VERSION 5.7 ;
  NOWIREEXTENSIONATPIN ON ;
  DIVIDERCHAR "/" ;
  BUSBITCHARS "[]" ;
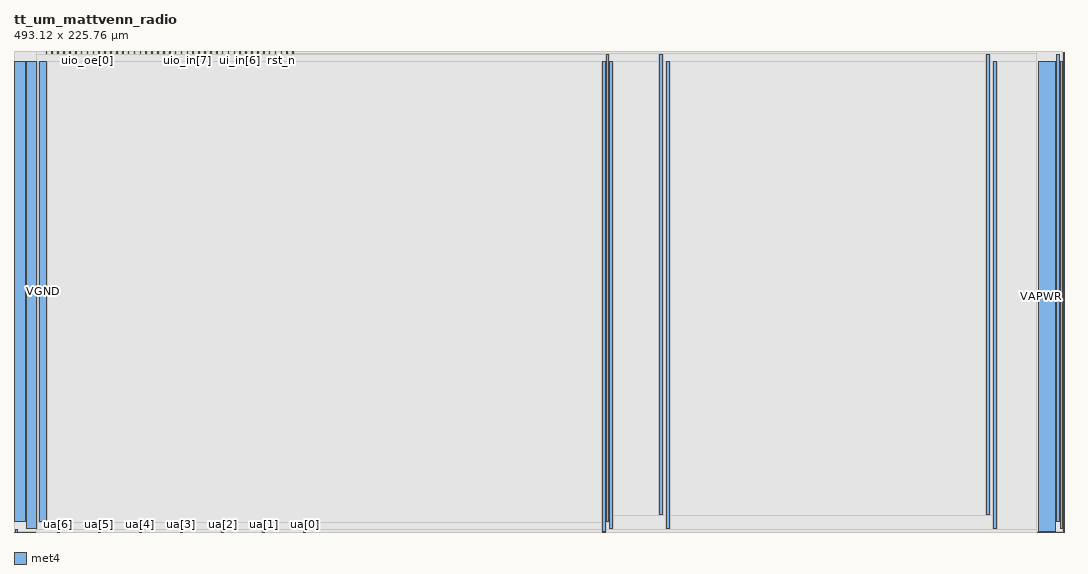
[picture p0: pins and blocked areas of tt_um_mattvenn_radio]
MACRO tt_um_mattvenn_radio
  CLASS BLOCK ;
  FOREIGN tt_um_mattvenn_radio ;
  ORIGIN 0.000 0.000 ;
  SIZE 493.120 BY 225.760 ;
  PIN clk
    ANTENNAGATEAREA 1.704000 ;
    PORT
      LAYER met4 ;
        RECT 128.190 224.760 128.490 225.760 ;
    END
  END clk
  PIN ena
    PORT
      LAYER met4 ;
        RECT 130.950 224.760 131.250 225.760 ;
    END
  END ena
  PIN rst_n
    ANTENNAGATEAREA 0.213000 ;
    PORT
      LAYER met4 ;
        RECT 125.430 224.760 125.730 225.760 ;
    END
  END rst_n
  PIN ua[0]
    PORT
      LAYER met4 ;
        RECT 136.170 0.000 137.070 1.000 ;
    END
  END ua[0]
  PIN ua[1]
    PORT
      LAYER met4 ;
        RECT 116.850 0.000 117.750 1.000 ;
    END
  END ua[1]
  PIN ua[2]
    ANTENNADIFFAREA 1.800000 ;
    PORT
      LAYER met4 ;
        RECT 97.530 0.000 98.430 1.000 ;
    END
  END ua[2]
  PIN ua[3]
    ANTENNADIFFAREA 29.456999 ;
    PORT
      LAYER met4 ;
        RECT 78.210 0.000 79.110 1.000 ;
    END
  END ua[3]
  PIN ua[4]
    ANTENNADIFFAREA 29.456999 ;
    PORT
      LAYER met4 ;
        RECT 58.890 0.000 59.790 1.000 ;
    END
  END ua[4]
  PIN ua[5]
    PORT
      LAYER met4 ;
        RECT 39.570 0.000 40.470 1.000 ;
    END
  END ua[5]
  PIN ua[6]
    PORT
      LAYER met4 ;
        RECT 20.250 0.000 21.150 1.000 ;
    END
  END ua[6]
  PIN ua[7]
    PORT
      LAYER met4 ;
        RECT 0.930 0.000 1.830 1.000 ;
    END
  END ua[7]
  PIN ui_in[0]
    ANTENNAGATEAREA 0.213000 ;
    PORT
      LAYER met4 ;
        RECT 122.670 224.760 122.970 225.760 ;
    END
  END ui_in[0]
  PIN ui_in[1]
    ANTENNAGATEAREA 0.213000 ;
    PORT
      LAYER met4 ;
        RECT 119.910 224.760 120.210 225.760 ;
    END
  END ui_in[1]
  PIN ui_in[2]
    ANTENNAGATEAREA 0.213000 ;
    PORT
      LAYER met4 ;
        RECT 117.150 224.760 117.450 225.760 ;
    END
  END ui_in[2]
  PIN ui_in[3]
    ANTENNAGATEAREA 0.213000 ;
    PORT
      LAYER met4 ;
        RECT 114.390 224.760 114.690 225.760 ;
    END
  END ui_in[3]
  PIN ui_in[4]
    ANTENNAGATEAREA 0.213000 ;
    PORT
      LAYER met4 ;
        RECT 111.630 224.760 111.930 225.760 ;
    END
  END ui_in[4]
  PIN ui_in[5]
    ANTENNAGATEAREA 0.213000 ;
    PORT
      LAYER met4 ;
        RECT 108.870 224.760 109.170 225.760 ;
    END
  END ui_in[5]
  PIN ui_in[6]
    ANTENNAGATEAREA 0.213000 ;
    PORT
      LAYER met4 ;
        RECT 106.110 224.760 106.410 225.760 ;
    END
  END ui_in[6]
  PIN ui_in[7]
    ANTENNAGATEAREA 0.213000 ;
    PORT
      LAYER met4 ;
        RECT 103.350 224.760 103.650 225.760 ;
    END
  END ui_in[7]
  PIN uio_in[0]
    ANTENNAGATEAREA 0.213000 ;
    PORT
      LAYER met4 ;
        RECT 100.590 224.760 100.890 225.760 ;
    END
  END uio_in[0]
  PIN uio_in[1]
    ANTENNAGATEAREA 0.213000 ;
    PORT
      LAYER met4 ;
        RECT 97.830 224.760 98.130 225.760 ;
    END
  END uio_in[1]
  PIN uio_in[2]
    ANTENNAGATEAREA 0.213000 ;
    PORT
      LAYER met4 ;
        RECT 95.070 224.760 95.370 225.760 ;
    END
  END uio_in[2]
  PIN uio_in[3]
    ANTENNAGATEAREA 0.213000 ;
    PORT
      LAYER met4 ;
        RECT 92.310 224.760 92.610 225.760 ;
    END
  END uio_in[3]
  PIN uio_in[4]
    ANTENNAGATEAREA 0.213000 ;
    PORT
      LAYER met4 ;
        RECT 89.550 224.760 89.850 225.760 ;
    END
  END uio_in[4]
  PIN uio_in[5]
    ANTENNAGATEAREA 0.213000 ;
    PORT
      LAYER met4 ;
        RECT 86.790 224.760 87.090 225.760 ;
    END
  END uio_in[5]
  PIN uio_in[6]
    ANTENNAGATEAREA 0.213000 ;
    PORT
      LAYER met4 ;
        RECT 84.030 224.760 84.330 225.760 ;
    END
  END uio_in[6]
  PIN uio_in[7]
    ANTENNAGATEAREA 0.213000 ;
    PORT
      LAYER met4 ;
        RECT 81.270 224.760 81.570 225.760 ;
    END
  END uio_in[7]
  PIN uio_oe[0]
    PORT
      LAYER met4 ;
        RECT 34.350 224.760 34.650 225.760 ;
    END
  END uio_oe[0]
  PIN uio_oe[1]
    PORT
      LAYER met4 ;
        RECT 31.590 224.760 31.890 225.760 ;
    END
  END uio_oe[1]
  PIN uio_oe[2]
    PORT
      LAYER met4 ;
        RECT 28.830 224.760 29.130 225.760 ;
    END
  END uio_oe[2]
  PIN uio_oe[3]
    ANTENNADIFFAREA 0.702900 ;
    PORT
      LAYER met4 ;
        RECT 26.070 224.760 26.370 225.760 ;
    END
  END uio_oe[3]
  PIN uio_oe[4]
    ANTENNADIFFAREA 0.702900 ;
    PORT
      LAYER met4 ;
        RECT 23.310 224.760 23.610 225.760 ;
    END
  END uio_oe[4]
  PIN uio_oe[5]
    ANTENNADIFFAREA 0.702900 ;
    PORT
      LAYER met4 ;
        RECT 20.550 224.760 20.850 225.760 ;
    END
  END uio_oe[5]
  PIN uio_oe[6]
    ANTENNADIFFAREA 0.702900 ;
    PORT
      LAYER met4 ;
        RECT 17.790 224.760 18.090 225.760 ;
    END
  END uio_oe[6]
  PIN uio_oe[7]
    ANTENNADIFFAREA 0.702900 ;
    PORT
      LAYER met4 ;
        RECT 15.030 224.760 15.330 225.760 ;
    END
  END uio_oe[7]
  PIN uio_out[0]
    PORT
      LAYER met4 ;
        RECT 56.430 224.760 56.730 225.760 ;
    END
  END uio_out[0]
  PIN uio_out[1]
    PORT
      LAYER met4 ;
        RECT 53.670 224.760 53.970 225.760 ;
    END
  END uio_out[1]
  PIN uio_out[2]
    PORT
      LAYER met4 ;
        RECT 50.910 224.760 51.210 225.760 ;
    END
  END uio_out[2]
  PIN uio_out[3]
    ANTENNADIFFAREA 0.702900 ;
    PORT
      LAYER met4 ;
        RECT 48.150 224.760 48.450 225.760 ;
    END
  END uio_out[3]
  PIN uio_out[4]
    ANTENNADIFFAREA 0.702900 ;
    PORT
      LAYER met4 ;
        RECT 45.390 224.760 45.690 225.760 ;
    END
  END uio_out[4]
  PIN uio_out[5]
    ANTENNADIFFAREA 0.702900 ;
    PORT
      LAYER met4 ;
        RECT 42.630 224.760 42.930 225.760 ;
    END
  END uio_out[5]
  PIN uio_out[6]
    ANTENNADIFFAREA 0.702900 ;
    PORT
      LAYER met4 ;
        RECT 39.870 224.760 40.170 225.760 ;
    END
  END uio_out[6]
  PIN uio_out[7]
    ANTENNADIFFAREA 0.702900 ;
    PORT
      LAYER met4 ;
        RECT 37.110 224.760 37.410 225.760 ;
    END
  END uio_out[7]
  PIN uo_out[0]
    ANTENNADIFFAREA 0.702900 ;
    PORT
      LAYER met4 ;
        RECT 78.510 224.760 78.810 225.760 ;
    END
  END uo_out[0]
  PIN uo_out[1]
    ANTENNADIFFAREA 0.702900 ;
    PORT
      LAYER met4 ;
        RECT 75.750 224.760 76.050 225.760 ;
    END
  END uo_out[1]
  PIN uo_out[2]
    ANTENNADIFFAREA 0.702900 ;
    PORT
      LAYER met4 ;
        RECT 72.990 224.760 73.290 225.760 ;
    END
  END uo_out[2]
  PIN uo_out[3]
    ANTENNADIFFAREA 0.702900 ;
    PORT
      LAYER met4 ;
        RECT 70.230 224.760 70.530 225.760 ;
    END
  END uo_out[3]
  PIN uo_out[4]
    ANTENNADIFFAREA 0.702900 ;
    PORT
      LAYER met4 ;
        RECT 67.470 224.760 67.770 225.760 ;
    END
  END uo_out[4]
  PIN uo_out[5]
    ANTENNADIFFAREA 0.702900 ;
    PORT
      LAYER met4 ;
        RECT 64.710 224.760 65.010 225.760 ;
    END
  END uo_out[5]
  PIN uo_out[6]
    ANTENNADIFFAREA 0.702900 ;
    PORT
      LAYER met4 ;
        RECT 61.950 224.760 62.250 225.760 ;
    END
  END uo_out[6]
  PIN uo_out[7]
    ANTENNADIFFAREA 0.702900 ;
    PORT
      LAYER met4 ;
        RECT 59.190 224.760 59.490 225.760 ;
    END
  END uo_out[7]
  PIN VGND
    USE GROUND ;
    PORT
      LAYER met4 ;
        RECT 12.000 5.000 15.100 220.760 ;
    END
    PORT
      LAYER met4 ;
        RECT 489.720 5.000 490.920 224.400 ;
    END
    PORT
      LAYER met4 ;
        RECT 278.200 5.000 279.400 224.400 ;
    END
    PORT
      LAYER met4 ;
        RECT 302.960 8.080 304.560 224.400 ;
    END
    PORT
      LAYER met4 ;
        RECT 456.560 8.080 458.160 224.400 ;
    END
  END VGND
  PIN VDPWR
    USE POWER ;
    ANTENNAGATEAREA 1797.139526 ;
    ANTENNADIFFAREA 2899.035645 ;
    PORT
      LAYER met4 ;
        RECT 5.800 1.700 10.500 220.760 ;
    END
    PORT
      LAYER met4 ;
        RECT 491.420 1.700 492.620 220.760 ;
    END
    PORT
      LAYER met4 ;
        RECT 279.900 1.700 281.100 220.760 ;
    END
    PORT
      LAYER met4 ;
        RECT 306.260 1.700 307.860 220.760 ;
    END
    PORT
      LAYER met4 ;
        RECT 459.860 1.700 461.460 220.760 ;
    END
  END VDPWR
  PIN VAPWR
    USE POWER ;
    ANTENNAGATEAREA 6748.000000 ;
    ANTENNADIFFAREA 188.743988 ;
    PORT
      LAYER met4 ;
        RECT 481.000 0.400 489.220 220.760 ;
    END
    PORT
      LAYER met4 ;
        RECT 276.500 0.400 277.700 220.760 ;
    END
    PORT
      LAYER met4 ;
        RECT 0.300 5.000 5.300 220.760 ;
    END
  END VAPWR
  OBS
      LAYER nwell ;
        RECT 1.170 3.200 477.170 215.125 ;
      LAYER li1 ;
        RECT 1.300 3.330 476.980 215.125 ;
      LAYER met1 ;
        RECT 0.000 2.800 481.970 221.460 ;
      LAYER met2 ;
        RECT 0.000 0.200 481.940 224.975 ;
      LAYER met3 ;
        RECT 0.000 0.200 492.620 225.560 ;
      LAYER met4 ;
        RECT 10.500 224.360 14.630 225.535 ;
        RECT 15.730 224.360 17.390 225.535 ;
        RECT 18.490 224.360 20.150 225.535 ;
        RECT 21.250 224.360 22.910 225.535 ;
        RECT 24.010 224.360 25.670 225.535 ;
        RECT 26.770 224.360 28.430 225.535 ;
        RECT 29.530 224.360 31.190 225.535 ;
        RECT 32.290 224.360 33.950 225.535 ;
        RECT 35.050 224.360 36.710 225.535 ;
        RECT 37.810 224.360 39.470 225.535 ;
        RECT 40.570 224.360 42.230 225.535 ;
        RECT 43.330 224.360 44.990 225.535 ;
        RECT 46.090 224.360 47.750 225.535 ;
        RECT 48.850 224.360 50.510 225.535 ;
        RECT 51.610 224.360 53.270 225.535 ;
        RECT 54.370 224.360 56.030 225.535 ;
        RECT 57.130 224.360 58.790 225.535 ;
        RECT 59.890 224.360 61.550 225.535 ;
        RECT 62.650 224.360 64.310 225.535 ;
        RECT 65.410 224.360 67.070 225.535 ;
        RECT 68.170 224.360 69.830 225.535 ;
        RECT 70.930 224.360 72.590 225.535 ;
        RECT 73.690 224.360 75.350 225.535 ;
        RECT 76.450 224.360 78.110 225.535 ;
        RECT 79.210 224.360 80.870 225.535 ;
        RECT 81.970 224.360 83.630 225.535 ;
        RECT 84.730 224.360 86.390 225.535 ;
        RECT 87.490 224.360 89.150 225.535 ;
        RECT 90.250 224.360 91.910 225.535 ;
        RECT 93.010 224.360 94.670 225.535 ;
        RECT 95.770 224.360 97.430 225.535 ;
        RECT 98.530 224.360 100.190 225.535 ;
        RECT 101.290 224.360 102.950 225.535 ;
        RECT 104.050 224.360 105.710 225.535 ;
        RECT 106.810 224.360 108.470 225.535 ;
        RECT 109.570 224.360 111.230 225.535 ;
        RECT 112.330 224.360 113.990 225.535 ;
        RECT 115.090 224.360 116.750 225.535 ;
        RECT 117.850 224.360 119.510 225.535 ;
        RECT 120.610 224.360 122.270 225.535 ;
        RECT 123.370 224.360 125.030 225.535 ;
        RECT 126.130 224.360 127.790 225.535 ;
        RECT 128.890 224.360 130.550 225.535 ;
        RECT 131.650 224.800 480.365 225.535 ;
        RECT 131.650 224.360 277.800 224.800 ;
        RECT 10.500 221.160 277.800 224.360 ;
        RECT 279.800 221.160 302.560 224.800 ;
        RECT 10.900 4.600 11.600 221.160 ;
        RECT 15.500 4.600 276.100 221.160 ;
        RECT 281.500 7.680 302.560 221.160 ;
        RECT 304.960 221.160 456.160 224.800 ;
        RECT 304.960 7.680 305.860 221.160 ;
        RECT 10.900 1.400 276.100 4.600 ;
        RECT 10.900 1.300 19.850 1.400 ;
        RECT 10.500 0.000 19.850 1.300 ;
        RECT 21.550 0.000 39.170 1.400 ;
        RECT 40.870 0.000 58.490 1.400 ;
        RECT 60.190 0.000 77.810 1.400 ;
        RECT 79.510 0.000 97.130 1.400 ;
        RECT 98.830 0.000 116.450 1.400 ;
        RECT 118.150 0.000 135.770 1.400 ;
        RECT 137.470 0.000 276.100 1.400 ;
        RECT 278.100 1.300 279.500 4.600 ;
        RECT 281.500 1.300 305.860 7.680 ;
        RECT 308.260 7.680 456.160 221.160 ;
        RECT 458.560 221.160 480.365 224.800 ;
        RECT 458.560 7.680 459.460 221.160 ;
        RECT 308.260 1.300 459.460 7.680 ;
        RECT 461.860 1.300 480.365 221.160 ;
        RECT 278.100 0.000 480.365 1.300 ;
  END
END tt_um_mattvenn_radio
END LIBRARY

